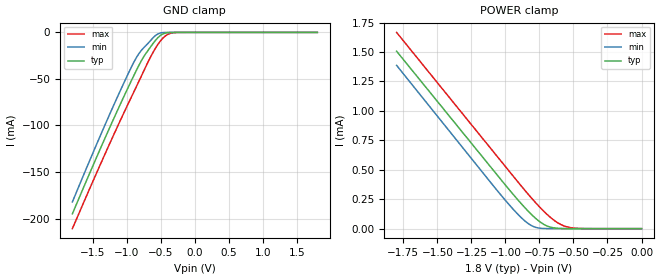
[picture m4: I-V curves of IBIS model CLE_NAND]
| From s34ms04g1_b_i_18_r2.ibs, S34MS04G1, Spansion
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|   Model CLE_NAND
[Model]   CLE_NAND
Model_type   Input
Vinl = 0.360V
Vinh = 1.440V
| variable   typ   min   max
C_comp   2.20pF   1.98pF   2.64pF
| variable   typ   min   max
[Temperature Range]  25.00   -30.00   85.00
[Voltage Range]   1.800   1.700   1.950
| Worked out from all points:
|   GND clamp passes 1 mA (typ) near -0.44 V on its own axis
|   POWER clamp passes 1 mA (typ) near -1.44 V on its own axis
[GND_clamp]
| voltage   I(typ)   I(min)   I(max)
-1.8V     -194.9mA   -182.1mA   -210.8mA
-1.26V    -103.6mA   -89.29mA   -120.8mA
-1.008V   -63.4mA    -48.75mA   -80.96mA
-864mV    -41.46mA   -27.63mA   -58.91mA
-756mV    -26.66mA   -16.84mA   -42.22mA
-648mV    -15.32mA   -8.452mA   -26.02mA
-576mV    -8.323mA   -3.164mA   -16.63mA
-504mV    -3.159mA   -587.5uA   -9.02mA
-432mV    -705.2uA   -55.34uA   -3.713mA
-360mV    -94.02uA   -2.944uA   -1.022mA
-252mV    -2.155uA   -17.44nA   -71.51uA
1.8V      140.8pA    79.49pA    15.92nA
[POWER_clamp]
| voltage   I(typ)   I(min)   I(max)
-1.8V     1.507mA    1.387mA    1.667mA
-1.026V   406.7uA    275.8uA    564.2uA
-900mV    233.3uA    112.2uA    385.1uA
-828mV    142.8uA    39.6uA     285.9uA
-774mV    83.46uA    9.835uA    215.4uA
-702mV    26.5uA     788.5nA    129.7uA
-630mV    4.493uA    62.15nA    60.59uA
-558mV    538.1nA    3.703nA    18.69uA
-450mV    16.7nA     132.3pA    1.525uA
0V        0A         0A         0A
